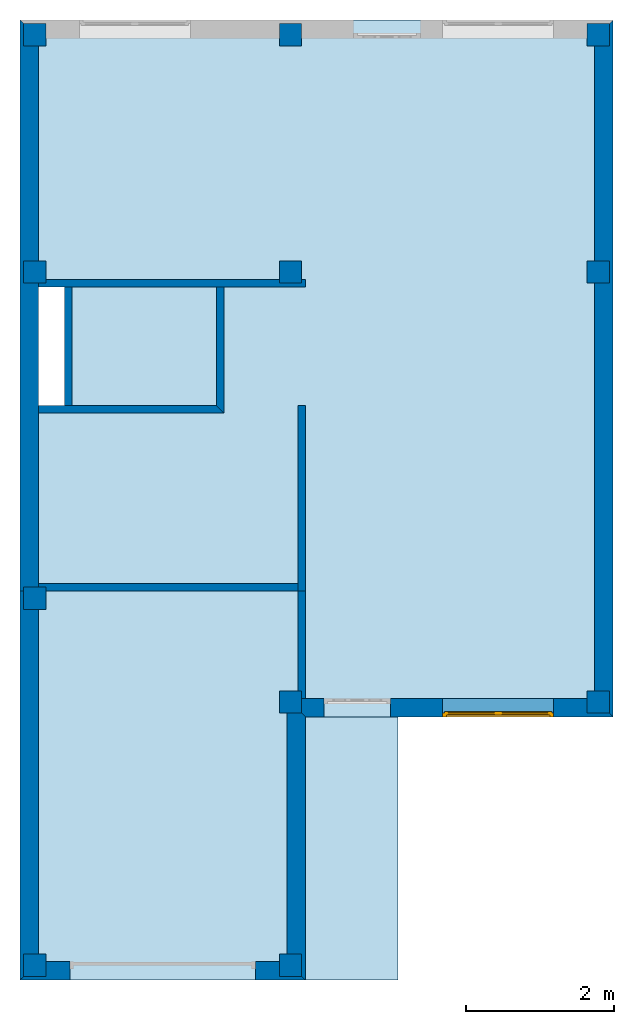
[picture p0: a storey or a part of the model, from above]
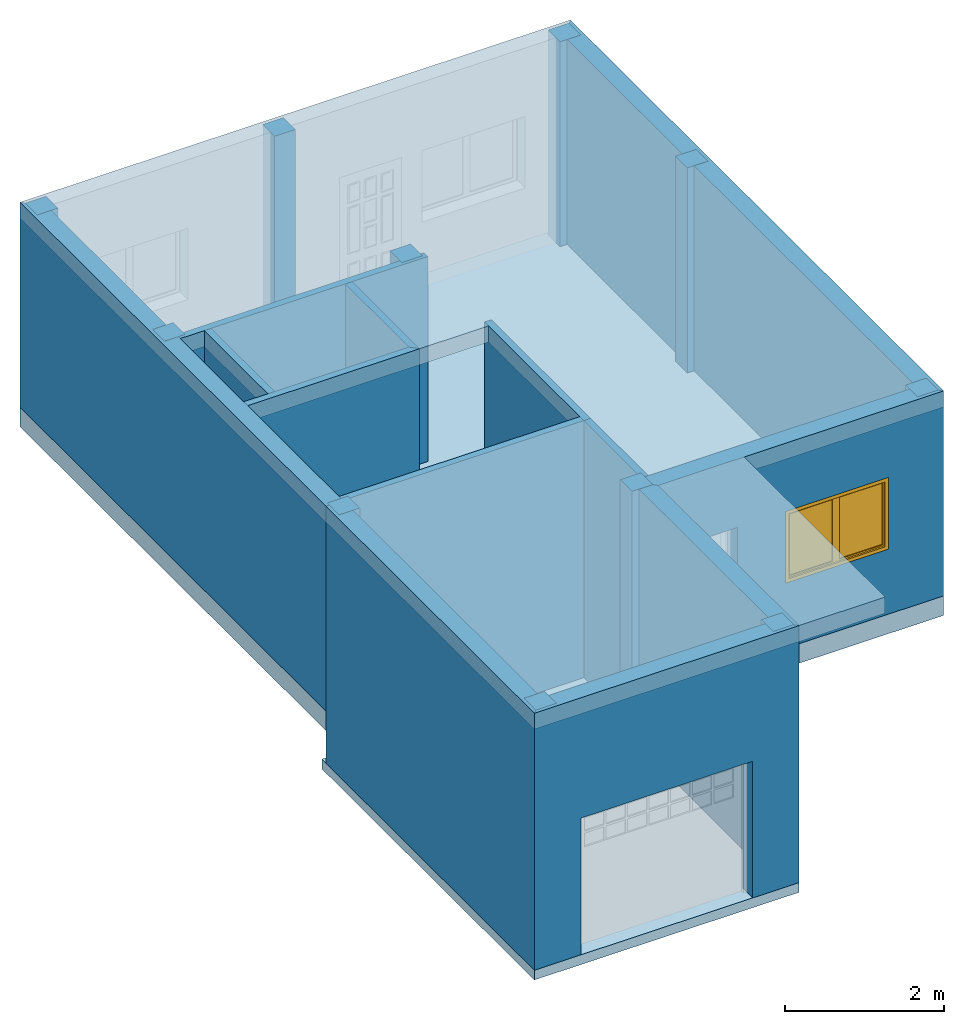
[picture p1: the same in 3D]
Properties of the parts of a building model (IFC2X3)

# File
Description: ViewDefinition [CoordinationView], Option [Filter: VisibleElements]
File name: C:\Guillermo\Un proyecto con CYPE\Archicad\Fichero_IFC.ifc
Time: 2010-10-11T18:05:03
Author: Architect
Organization: Building Designer Office
Written by: PreProc - EDM 5.0
Made in: ArchiCAD 13.00 Release 1. Windows Build Number of the Ifc 2x3 interface: 64125 (21-07-2009)
Authorization: The authorising person

# IfcProject, Por defecto Proyecto
GSPset_TimeStamp - GS_TimeStamp: 1026830

# IfcSite, Por defecto Sitio
RefLatitude: 40, 25, 0; RefLongitude: -3, -43, 0

# IfcBuildingStorey (4)
In: Por defecto Edificio
Name | Elevation (mm)
Planta Baja | 0
Primera | 3150
Azotea | 6300
Cubierta | 9100

# IfcColumn (23)
Material: Hormigón armado
Name | In
Pilar-001 | Planta Baja
Pilar-002 | Planta Baja
Pilar-003 | Planta Baja
Pilar-004 | Planta Baja
Pilar-005 | Planta Baja
Pilar-006 | Planta Baja
Pilar-007 | Planta Baja
Pilar-008 | Planta Baja
Pilar-009 | Planta Baja
Pilar-010 | Planta Baja
Pilar-011 | Planta Baja
Pilar-011 | Primera
Pilar-010 | Primera
Pilar-003 | Primera
Pilar-004 | Primera
Pilar-005 | Primera
Pilar-006 | Primera
Pilar-007 | Primera
Pilar-008 | Primera
Pilar-009 | Primera
Pilar-005 | Azotea
Pilar-007 | Azotea
Pilar-008 | Azotea

# IfcDoor: P1 Entrada 13, P02
In: Planta Baja
Type - OperationType: SINGLE_SWING_LEFT; ParameterTakesPrecedence: no; Sizeable: no
Type - IfcDoorLiningProperties - LiningDepth: 75 mm; LiningThickness: 50 mm; ThresholdDepth: 10 mm; ThresholdThickness: 12 mm; ThresholdOffset: 65 mm
Type - IfcDoorPanelProperties - PanelDepth: 44 mm; PanelOperation: SWINGING; PanelPosition: MIDDLE
OverallHeight: 2100 mm; OverallWidth: 900 mm

# IfcDoor: P1 Entrada 13, P03
In: Planta Baja
Type - OperationType: SINGLE_SWING_RIGHT; ParameterTakesPrecedence: no; Sizeable: no
Type - IfcDoorLiningProperties - LiningDepth: 75 mm; LiningThickness: 50 mm; ThresholdDepth: 10 mm; ThresholdThickness: 12 mm; ThresholdOffset: 65 mm
Type - IfcDoorPanelProperties - PanelDepth: 44 mm; PanelOperation: SWINGING; PanelPosition: MIDDLE
OverallHeight: 2100 mm; OverallWidth: 900 mm

# IfcDoor: P1 Garaje 2 13, P01
In: Planta Baja
Type - OperationType: ROLLINGUP; ParameterTakesPrecedence: no; Sizeable: no
Type - IfcDoorLiningProperties - LiningDepth: 100 mm; LiningThickness: 50 mm; ThresholdDepth: 0.00001 mm; ThresholdThickness: 12 mm; ThresholdOffset: 100 mm
Type - IfcDoorPanelProperties - PanelDepth: 40 mm; PanelOperation: ROLLINGUP; PanelPosition: MIDDLE
OverallHeight: 2100 mm; OverallWidth: 2500 mm

# IfcSlab (5)
PredefinedType: FLOOR
Name | In | Material
Forj-001 | Planta Baja | Hormigón armado 300 mm
Forj-002 | Planta Baja | Hormigón armado 250 mm
Forj-003 | Planta Baja | Hormigón en masa 150 mm
Forj-005 | Primera | Hormigón armado 250 mm
Forj-006 | Azotea | Hormigón armado 250 mm

# IfcWallStandardCase: Bloque mampostería 100 (16)
Type - ElementType: Bloque mampostería 100; Material: Bloque mampostería 100 mm
Name | In
2 x Muro-007 | Planta Baja
2 x Muro-008 | Planta Baja
Muro-009 | Planta Baja
Muro-010 | Planta Baja
Muro-011 | Planta Baja
Muro-007 | Primera
Muro-008 | Primera
Muro-009 | Primera
Muro-010 | Primera
Muro-011 | Primera
Muro-012 | Primera
Muro-013 | Primera
Muro-017 | Azotea
Muro-018 | Azotea

# IfcWallStandardCase: Bloque mampostería 250 (25)
Type - ElementType: Bloque mampostería 250; Material: Bloque mampostería 250 mm
Name | In
Muro-001 | Planta Baja
Muro-002 | Planta Baja
2 x Muro-003 | Planta Baja
Muro-004 | Planta Baja
Muro-005 | Planta Baja
Muro-006 | Planta Baja
2 x Muro-009 | Primera
2 x Muro-010 | Primera
2 x Muro-011 | Primera
Muro-012 | Primera
Muro-013 | Primera
Muro-014 | Primera
Muro-014 | Azotea
Muro-015 | Azotea
Muro-016 | Azotea
Muro-017 | Azotea
Muro-009 | Azotea
Muro-010 | Azotea
Muro-011 | Azotea
Muro-012 | Azotea
Muro-013 | Azotea

# IfcWindow: V1 Practicable DivH 13 (2)
Type - OperationType: SINGLE_PANEL; ParameterTakesPrecedence: no; Sizeable: no
Type - IfcWindowLiningProperties - LiningDepth: 50 mm; LiningThickness: 50 mm
Type - IfcWindowPanelProperties - PanelPosition: MIDDLE; FrameDepth: 50 mm; FrameThickness: 50 mm
OverallHeight: 1100 mm; OverallWidth: 800 mm
Name | In
V07 | Primera
V07 | Azotea

# IfcWindow: V2 Practicable 13 (8)
Type - OperationType: SINGLE_PANEL; ParameterTakesPrecedence: no; Sizeable: no
Type - IfcWindowLiningProperties - LiningDepth: 50 mm; LiningThickness: 50 mm
Type - IfcWindowPanelProperties - PanelPosition: MIDDLE; FrameDepth: 50 mm; FrameThickness: 50 mm
OverallHeight: 1100 mm; OverallWidth: 1500 mm
Name | In
V03 | Planta Baja
V01 | Planta Baja
V02 | Planta Baja
V03 | Primera
V04 | Primera
V05 | Primera
V06 | Primera
V04 | Azotea
